VERSION 5.7 ;
BUSBITCHARS "[]" ;
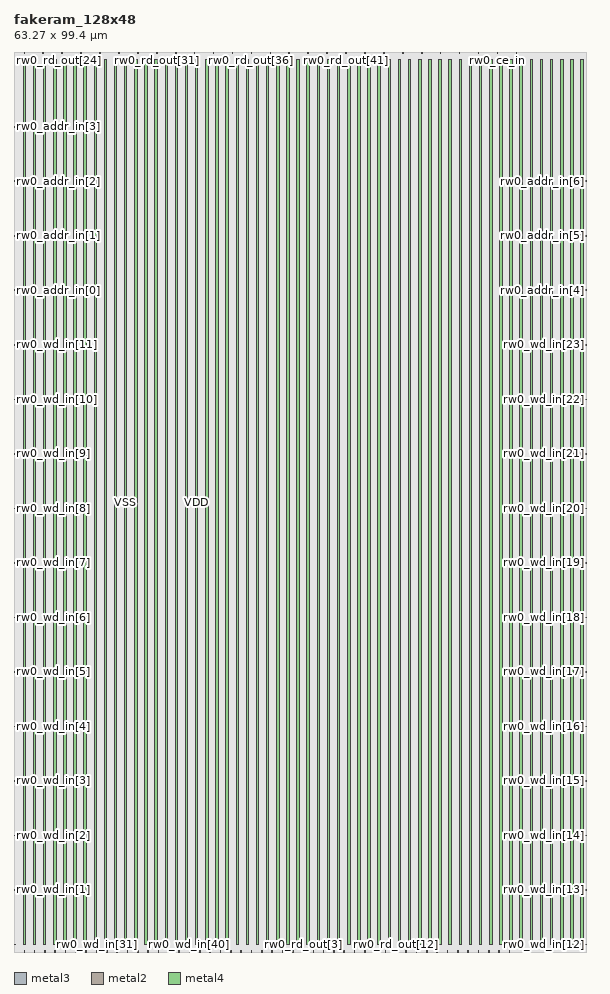
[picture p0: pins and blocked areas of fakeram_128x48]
MACRO fakeram_128x48
  FOREIGN fakeram_128x48 0 0 ;
  SYMMETRY X Y R90 ;
  SIZE 63.270 BY 99.400 ;
  CLASS BLOCK ;
  PIN rw0_wd_in[0]
    DIRECTION INPUT ;
    USE SIGNAL ;
    SHAPE ABUTMENT ;
    PORT
      LAYER metal3 ;
      RECT 0.000 0.805 0.210 0.875 ;
    END
  END rw0_wd_in[0]
  PIN rw0_wd_in[1]
    DIRECTION INPUT ;
    USE SIGNAL ;
    SHAPE ABUTMENT ;
    PORT
      LAYER metal3 ;
      RECT 0.000 6.825 0.210 6.895 ;
    END
  END rw0_wd_in[1]
  PIN rw0_wd_in[2]
    DIRECTION INPUT ;
    USE SIGNAL ;
    SHAPE ABUTMENT ;
    PORT
      LAYER metal3 ;
      RECT 0.000 12.845 0.210 12.915 ;
    END
  END rw0_wd_in[2]
  PIN rw0_wd_in[3]
    DIRECTION INPUT ;
    USE SIGNAL ;
    SHAPE ABUTMENT ;
    PORT
      LAYER metal3 ;
      RECT 0.000 18.865 0.210 18.935 ;
    END
  END rw0_wd_in[3]
  PIN rw0_wd_in[4]
    DIRECTION INPUT ;
    USE SIGNAL ;
    SHAPE ABUTMENT ;
    PORT
      LAYER metal3 ;
      RECT 0.000 24.885 0.210 24.955 ;
    END
  END rw0_wd_in[4]
  PIN rw0_wd_in[5]
    DIRECTION INPUT ;
    USE SIGNAL ;
    SHAPE ABUTMENT ;
    PORT
      LAYER metal3 ;
      RECT 0.000 30.905 0.210 30.975 ;
    END
  END rw0_wd_in[5]
  PIN rw0_wd_in[6]
    DIRECTION INPUT ;
    USE SIGNAL ;
    SHAPE ABUTMENT ;
    PORT
      LAYER metal3 ;
      RECT 0.000 36.925 0.210 36.995 ;
    END
  END rw0_wd_in[6]
  PIN rw0_wd_in[7]
    DIRECTION INPUT ;
    USE SIGNAL ;
    SHAPE ABUTMENT ;
    PORT
      LAYER metal3 ;
      RECT 0.000 42.945 0.210 43.015 ;
    END
  END rw0_wd_in[7]
  PIN rw0_wd_in[8]
    DIRECTION INPUT ;
    USE SIGNAL ;
    SHAPE ABUTMENT ;
    PORT
      LAYER metal3 ;
      RECT 0.000 48.965 0.210 49.035 ;
    END
  END rw0_wd_in[8]
  PIN rw0_wd_in[9]
    DIRECTION INPUT ;
    USE SIGNAL ;
    SHAPE ABUTMENT ;
    PORT
      LAYER metal3 ;
      RECT 0.000 54.985 0.210 55.055 ;
    END
  END rw0_wd_in[9]
  PIN rw0_wd_in[10]
    DIRECTION INPUT ;
    USE SIGNAL ;
    SHAPE ABUTMENT ;
    PORT
      LAYER metal3 ;
      RECT 0.000 61.005 0.210 61.075 ;
    END
  END rw0_wd_in[10]
  PIN rw0_wd_in[11]
    DIRECTION INPUT ;
    USE SIGNAL ;
    SHAPE ABUTMENT ;
    PORT
      LAYER metal3 ;
      RECT 0.000 67.025 0.210 67.095 ;
    END
  END rw0_wd_in[11]
  PIN rw0_wd_in[12]
    DIRECTION INPUT ;
    USE SIGNAL ;
    SHAPE ABUTMENT ;
    PORT
      LAYER metal3 ;
      RECT 63.060 0.805 63.270 0.875 ;
    END
  END rw0_wd_in[12]
  PIN rw0_wd_in[13]
    DIRECTION INPUT ;
    USE SIGNAL ;
    SHAPE ABUTMENT ;
    PORT
      LAYER metal3 ;
      RECT 63.060 6.825 63.270 6.895 ;
    END
  END rw0_wd_in[13]
  PIN rw0_wd_in[14]
    DIRECTION INPUT ;
    USE SIGNAL ;
    SHAPE ABUTMENT ;
    PORT
      LAYER metal3 ;
      RECT 63.060 12.845 63.270 12.915 ;
    END
  END rw0_wd_in[14]
  PIN rw0_wd_in[15]
    DIRECTION INPUT ;
    USE SIGNAL ;
    SHAPE ABUTMENT ;
    PORT
      LAYER metal3 ;
      RECT 63.060 18.865 63.270 18.935 ;
    END
  END rw0_wd_in[15]
  PIN rw0_wd_in[16]
    DIRECTION INPUT ;
    USE SIGNAL ;
    SHAPE ABUTMENT ;
    PORT
      LAYER metal3 ;
      RECT 63.060 24.885 63.270 24.955 ;
    END
  END rw0_wd_in[16]
  PIN rw0_wd_in[17]
    DIRECTION INPUT ;
    USE SIGNAL ;
    SHAPE ABUTMENT ;
    PORT
      LAYER metal3 ;
      RECT 63.060 30.905 63.270 30.975 ;
    END
  END rw0_wd_in[17]
  PIN rw0_wd_in[18]
    DIRECTION INPUT ;
    USE SIGNAL ;
    SHAPE ABUTMENT ;
    PORT
      LAYER metal3 ;
      RECT 63.060 36.925 63.270 36.995 ;
    END
  END rw0_wd_in[18]
  PIN rw0_wd_in[19]
    DIRECTION INPUT ;
    USE SIGNAL ;
    SHAPE ABUTMENT ;
    PORT
      LAYER metal3 ;
      RECT 63.060 42.945 63.270 43.015 ;
    END
  END rw0_wd_in[19]
  PIN rw0_wd_in[20]
    DIRECTION INPUT ;
    USE SIGNAL ;
    SHAPE ABUTMENT ;
    PORT
      LAYER metal3 ;
      RECT 63.060 48.965 63.270 49.035 ;
    END
  END rw0_wd_in[20]
  PIN rw0_wd_in[21]
    DIRECTION INPUT ;
    USE SIGNAL ;
    SHAPE ABUTMENT ;
    PORT
      LAYER metal3 ;
      RECT 63.060 54.985 63.270 55.055 ;
    END
  END rw0_wd_in[21]
  PIN rw0_wd_in[22]
    DIRECTION INPUT ;
    USE SIGNAL ;
    SHAPE ABUTMENT ;
    PORT
      LAYER metal3 ;
      RECT 63.060 61.005 63.270 61.075 ;
    END
  END rw0_wd_in[22]
  PIN rw0_wd_in[23]
    DIRECTION INPUT ;
    USE SIGNAL ;
    SHAPE ABUTMENT ;
    PORT
      LAYER metal3 ;
      RECT 63.060 67.025 63.270 67.095 ;
    END
  END rw0_wd_in[23]
  PIN rw0_wd_in[24]
    DIRECTION INPUT ;
    USE SIGNAL ;
    SHAPE ABUTMENT ;
    PORT
      LAYER metal2 ;
      RECT 1.105 0.000 1.175 0.210 ;
    END
  END rw0_wd_in[24]
  PIN rw0_wd_in[25]
    DIRECTION INPUT ;
    USE SIGNAL ;
    SHAPE ABUTMENT ;
    PORT
      LAYER metal2 ;
      RECT 2.245 0.000 2.315 0.210 ;
    END
  END rw0_wd_in[25]
  PIN rw0_wd_in[26]
    DIRECTION INPUT ;
    USE SIGNAL ;
    SHAPE ABUTMENT ;
    PORT
      LAYER metal2 ;
      RECT 3.385 0.000 3.455 0.210 ;
    END
  END rw0_wd_in[26]
  PIN rw0_wd_in[27]
    DIRECTION INPUT ;
    USE SIGNAL ;
    SHAPE ABUTMENT ;
    PORT
      LAYER metal2 ;
      RECT 4.525 0.000 4.595 0.210 ;
    END
  END rw0_wd_in[27]
  PIN rw0_wd_in[28]
    DIRECTION INPUT ;
    USE SIGNAL ;
    SHAPE ABUTMENT ;
    PORT
      LAYER metal2 ;
      RECT 5.665 0.000 5.735 0.210 ;
    END
  END rw0_wd_in[28]
  PIN rw0_wd_in[29]
    DIRECTION INPUT ;
    USE SIGNAL ;
    SHAPE ABUTMENT ;
    PORT
      LAYER metal2 ;
      RECT 6.805 0.000 6.875 0.210 ;
    END
  END rw0_wd_in[29]
  PIN rw0_wd_in[30]
    DIRECTION INPUT ;
    USE SIGNAL ;
    SHAPE ABUTMENT ;
    PORT
      LAYER metal2 ;
      RECT 7.945 0.000 8.015 0.210 ;
    END
  END rw0_wd_in[30]
  PIN rw0_wd_in[31]
    DIRECTION INPUT ;
    USE SIGNAL ;
    SHAPE ABUTMENT ;
    PORT
      LAYER metal2 ;
      RECT 9.085 0.000 9.155 0.210 ;
    END
  END rw0_wd_in[31]
  PIN rw0_wd_in[32]
    DIRECTION INPUT ;
    USE SIGNAL ;
    SHAPE ABUTMENT ;
    PORT
      LAYER metal2 ;
      RECT 10.225 0.000 10.295 0.210 ;
    END
  END rw0_wd_in[32]
  PIN rw0_wd_in[33]
    DIRECTION INPUT ;
    USE SIGNAL ;
    SHAPE ABUTMENT ;
    PORT
      LAYER metal2 ;
      RECT 11.365 0.000 11.435 0.210 ;
    END
  END rw0_wd_in[33]
  PIN rw0_wd_in[34]
    DIRECTION INPUT ;
    USE SIGNAL ;
    SHAPE ABUTMENT ;
    PORT
      LAYER metal2 ;
      RECT 12.505 0.000 12.575 0.210 ;
    END
  END rw0_wd_in[34]
  PIN rw0_wd_in[35]
    DIRECTION INPUT ;
    USE SIGNAL ;
    SHAPE ABUTMENT ;
    PORT
      LAYER metal2 ;
      RECT 13.645 0.000 13.715 0.210 ;
    END
  END rw0_wd_in[35]
  PIN rw0_wd_in[36]
    DIRECTION INPUT ;
    USE SIGNAL ;
    SHAPE ABUTMENT ;
    PORT
      LAYER metal2 ;
      RECT 14.785 0.000 14.855 0.210 ;
    END
  END rw0_wd_in[36]
  PIN rw0_wd_in[37]
    DIRECTION INPUT ;
    USE SIGNAL ;
    SHAPE ABUTMENT ;
    PORT
      LAYER metal2 ;
      RECT 15.925 0.000 15.995 0.210 ;
    END
  END rw0_wd_in[37]
  PIN rw0_wd_in[38]
    DIRECTION INPUT ;
    USE SIGNAL ;
    SHAPE ABUTMENT ;
    PORT
      LAYER metal2 ;
      RECT 17.065 0.000 17.135 0.210 ;
    END
  END rw0_wd_in[38]
  PIN rw0_wd_in[39]
    DIRECTION INPUT ;
    USE SIGNAL ;
    SHAPE ABUTMENT ;
    PORT
      LAYER metal2 ;
      RECT 18.205 0.000 18.275 0.210 ;
    END
  END rw0_wd_in[39]
  PIN rw0_wd_in[40]
    DIRECTION INPUT ;
    USE SIGNAL ;
    SHAPE ABUTMENT ;
    PORT
      LAYER metal2 ;
      RECT 19.345 0.000 19.415 0.210 ;
    END
  END rw0_wd_in[40]
  PIN rw0_wd_in[41]
    DIRECTION INPUT ;
    USE SIGNAL ;
    SHAPE ABUTMENT ;
    PORT
      LAYER metal2 ;
      RECT 20.485 0.000 20.555 0.210 ;
    END
  END rw0_wd_in[41]
  PIN rw0_wd_in[42]
    DIRECTION INPUT ;
    USE SIGNAL ;
    SHAPE ABUTMENT ;
    PORT
      LAYER metal2 ;
      RECT 21.625 0.000 21.695 0.210 ;
    END
  END rw0_wd_in[42]
  PIN rw0_wd_in[43]
    DIRECTION INPUT ;
    USE SIGNAL ;
    SHAPE ABUTMENT ;
    PORT
      LAYER metal2 ;
      RECT 22.765 0.000 22.835 0.210 ;
    END
  END rw0_wd_in[43]
  PIN rw0_wd_in[44]
    DIRECTION INPUT ;
    USE SIGNAL ;
    SHAPE ABUTMENT ;
    PORT
      LAYER metal2 ;
      RECT 23.905 0.000 23.975 0.210 ;
    END
  END rw0_wd_in[44]
  PIN rw0_wd_in[45]
    DIRECTION INPUT ;
    USE SIGNAL ;
    SHAPE ABUTMENT ;
    PORT
      LAYER metal2 ;
      RECT 25.045 0.000 25.115 0.210 ;
    END
  END rw0_wd_in[45]
  PIN rw0_wd_in[46]
    DIRECTION INPUT ;
    USE SIGNAL ;
    SHAPE ABUTMENT ;
    PORT
      LAYER metal2 ;
      RECT 26.185 0.000 26.255 0.210 ;
    END
  END rw0_wd_in[46]
  PIN rw0_wd_in[47]
    DIRECTION INPUT ;
    USE SIGNAL ;
    SHAPE ABUTMENT ;
    PORT
      LAYER metal2 ;
      RECT 27.325 0.000 27.395 0.210 ;
    END
  END rw0_wd_in[47]
  PIN rw0_rd_out[0]
    DIRECTION OUTPUT ;
    USE SIGNAL ;
    SHAPE ABUTMENT ;
    PORT
      LAYER metal2 ;
      RECT 28.465 0.000 28.535 0.210 ;
    END
  END rw0_rd_out[0]
  PIN rw0_rd_out[1]
    DIRECTION OUTPUT ;
    USE SIGNAL ;
    SHAPE ABUTMENT ;
    PORT
      LAYER metal2 ;
      RECT 29.605 0.000 29.675 0.210 ;
    END
  END rw0_rd_out[1]
  PIN rw0_rd_out[2]
    DIRECTION OUTPUT ;
    USE SIGNAL ;
    SHAPE ABUTMENT ;
    PORT
      LAYER metal2 ;
      RECT 30.745 0.000 30.815 0.210 ;
    END
  END rw0_rd_out[2]
  PIN rw0_rd_out[3]
    DIRECTION OUTPUT ;
    USE SIGNAL ;
    SHAPE ABUTMENT ;
    PORT
      LAYER metal2 ;
      RECT 31.885 0.000 31.955 0.210 ;
    END
  END rw0_rd_out[3]
  PIN rw0_rd_out[4]
    DIRECTION OUTPUT ;
    USE SIGNAL ;
    SHAPE ABUTMENT ;
    PORT
      LAYER metal2 ;
      RECT 33.025 0.000 33.095 0.210 ;
    END
  END rw0_rd_out[4]
  PIN rw0_rd_out[5]
    DIRECTION OUTPUT ;
    USE SIGNAL ;
    SHAPE ABUTMENT ;
    PORT
      LAYER metal2 ;
      RECT 34.165 0.000 34.235 0.210 ;
    END
  END rw0_rd_out[5]
  PIN rw0_rd_out[6]
    DIRECTION OUTPUT ;
    USE SIGNAL ;
    SHAPE ABUTMENT ;
    PORT
      LAYER metal2 ;
      RECT 35.305 0.000 35.375 0.210 ;
    END
  END rw0_rd_out[6]
  PIN rw0_rd_out[7]
    DIRECTION OUTPUT ;
    USE SIGNAL ;
    SHAPE ABUTMENT ;
    PORT
      LAYER metal2 ;
      RECT 36.445 0.000 36.515 0.210 ;
    END
  END rw0_rd_out[7]
  PIN rw0_rd_out[8]
    DIRECTION OUTPUT ;
    USE SIGNAL ;
    SHAPE ABUTMENT ;
    PORT
      LAYER metal2 ;
      RECT 37.585 0.000 37.655 0.210 ;
    END
  END rw0_rd_out[8]
  PIN rw0_rd_out[9]
    DIRECTION OUTPUT ;
    USE SIGNAL ;
    SHAPE ABUTMENT ;
    PORT
      LAYER metal2 ;
      RECT 38.725 0.000 38.795 0.210 ;
    END
  END rw0_rd_out[9]
  PIN rw0_rd_out[10]
    DIRECTION OUTPUT ;
    USE SIGNAL ;
    SHAPE ABUTMENT ;
    PORT
      LAYER metal2 ;
      RECT 39.865 0.000 39.935 0.210 ;
    END
  END rw0_rd_out[10]
  PIN rw0_rd_out[11]
    DIRECTION OUTPUT ;
    USE SIGNAL ;
    SHAPE ABUTMENT ;
    PORT
      LAYER metal2 ;
      RECT 41.005 0.000 41.075 0.210 ;
    END
  END rw0_rd_out[11]
  PIN rw0_rd_out[12]
    DIRECTION OUTPUT ;
    USE SIGNAL ;
    SHAPE ABUTMENT ;
    PORT
      LAYER metal2 ;
      RECT 42.145 0.000 42.215 0.210 ;
    END
  END rw0_rd_out[12]
  PIN rw0_rd_out[13]
    DIRECTION OUTPUT ;
    USE SIGNAL ;
    SHAPE ABUTMENT ;
    PORT
      LAYER metal2 ;
      RECT 43.285 0.000 43.355 0.210 ;
    END
  END rw0_rd_out[13]
  PIN rw0_rd_out[14]
    DIRECTION OUTPUT ;
    USE SIGNAL ;
    SHAPE ABUTMENT ;
    PORT
      LAYER metal2 ;
      RECT 44.425 0.000 44.495 0.210 ;
    END
  END rw0_rd_out[14]
  PIN rw0_rd_out[15]
    DIRECTION OUTPUT ;
    USE SIGNAL ;
    SHAPE ABUTMENT ;
    PORT
      LAYER metal2 ;
      RECT 45.565 0.000 45.635 0.210 ;
    END
  END rw0_rd_out[15]
  PIN rw0_rd_out[16]
    DIRECTION OUTPUT ;
    USE SIGNAL ;
    SHAPE ABUTMENT ;
    PORT
      LAYER metal2 ;
      RECT 46.705 0.000 46.775 0.210 ;
    END
  END rw0_rd_out[16]
  PIN rw0_rd_out[17]
    DIRECTION OUTPUT ;
    USE SIGNAL ;
    SHAPE ABUTMENT ;
    PORT
      LAYER metal2 ;
      RECT 47.845 0.000 47.915 0.210 ;
    END
  END rw0_rd_out[17]
  PIN rw0_rd_out[18]
    DIRECTION OUTPUT ;
    USE SIGNAL ;
    SHAPE ABUTMENT ;
    PORT
      LAYER metal2 ;
      RECT 48.985 0.000 49.055 0.210 ;
    END
  END rw0_rd_out[18]
  PIN rw0_rd_out[19]
    DIRECTION OUTPUT ;
    USE SIGNAL ;
    SHAPE ABUTMENT ;
    PORT
      LAYER metal2 ;
      RECT 50.125 0.000 50.195 0.210 ;
    END
  END rw0_rd_out[19]
  PIN rw0_rd_out[20]
    DIRECTION OUTPUT ;
    USE SIGNAL ;
    SHAPE ABUTMENT ;
    PORT
      LAYER metal2 ;
      RECT 51.265 0.000 51.335 0.210 ;
    END
  END rw0_rd_out[20]
  PIN rw0_rd_out[21]
    DIRECTION OUTPUT ;
    USE SIGNAL ;
    SHAPE ABUTMENT ;
    PORT
      LAYER metal2 ;
      RECT 52.405 0.000 52.475 0.210 ;
    END
  END rw0_rd_out[21]
  PIN rw0_rd_out[22]
    DIRECTION OUTPUT ;
    USE SIGNAL ;
    SHAPE ABUTMENT ;
    PORT
      LAYER metal2 ;
      RECT 53.545 0.000 53.615 0.210 ;
    END
  END rw0_rd_out[22]
  PIN rw0_rd_out[23]
    DIRECTION OUTPUT ;
    USE SIGNAL ;
    SHAPE ABUTMENT ;
    PORT
      LAYER metal2 ;
      RECT 54.685 0.000 54.755 0.210 ;
    END
  END rw0_rd_out[23]
  PIN rw0_rd_out[24]
    DIRECTION OUTPUT ;
    USE SIGNAL ;
    SHAPE ABUTMENT ;
    PORT
      LAYER metal2 ;
      RECT 1.105 99.190 1.175 99.400 ;
    END
  END rw0_rd_out[24]
  PIN rw0_rd_out[25]
    DIRECTION OUTPUT ;
    USE SIGNAL ;
    SHAPE ABUTMENT ;
    PORT
      LAYER metal2 ;
      RECT 3.195 99.190 3.265 99.400 ;
    END
  END rw0_rd_out[25]
  PIN rw0_rd_out[26]
    DIRECTION OUTPUT ;
    USE SIGNAL ;
    SHAPE ABUTMENT ;
    PORT
      LAYER metal2 ;
      RECT 5.285 99.190 5.355 99.400 ;
    END
  END rw0_rd_out[26]
  PIN rw0_rd_out[27]
    DIRECTION OUTPUT ;
    USE SIGNAL ;
    SHAPE ABUTMENT ;
    PORT
      LAYER metal2 ;
      RECT 7.375 99.190 7.445 99.400 ;
    END
  END rw0_rd_out[27]
  PIN rw0_rd_out[28]
    DIRECTION OUTPUT ;
    USE SIGNAL ;
    SHAPE ABUTMENT ;
    PORT
      LAYER metal2 ;
      RECT 9.465 99.190 9.535 99.400 ;
    END
  END rw0_rd_out[28]
  PIN rw0_rd_out[29]
    DIRECTION OUTPUT ;
    USE SIGNAL ;
    SHAPE ABUTMENT ;
    PORT
      LAYER metal2 ;
      RECT 11.555 99.190 11.625 99.400 ;
    END
  END rw0_rd_out[29]
  PIN rw0_rd_out[30]
    DIRECTION OUTPUT ;
    USE SIGNAL ;
    SHAPE ABUTMENT ;
    PORT
      LAYER metal2 ;
      RECT 13.645 99.190 13.715 99.400 ;
    END
  END rw0_rd_out[30]
  PIN rw0_rd_out[31]
    DIRECTION OUTPUT ;
    USE SIGNAL ;
    SHAPE ABUTMENT ;
    PORT
      LAYER metal2 ;
      RECT 15.735 99.190 15.805 99.400 ;
    END
  END rw0_rd_out[31]
  PIN rw0_rd_out[32]
    DIRECTION OUTPUT ;
    USE SIGNAL ;
    SHAPE ABUTMENT ;
    PORT
      LAYER metal2 ;
      RECT 17.825 99.190 17.895 99.400 ;
    END
  END rw0_rd_out[32]
  PIN rw0_rd_out[33]
    DIRECTION OUTPUT ;
    USE SIGNAL ;
    SHAPE ABUTMENT ;
    PORT
      LAYER metal2 ;
      RECT 19.915 99.190 19.985 99.400 ;
    END
  END rw0_rd_out[33]
  PIN rw0_rd_out[34]
    DIRECTION OUTPUT ;
    USE SIGNAL ;
    SHAPE ABUTMENT ;
    PORT
      LAYER metal2 ;
      RECT 22.005 99.190 22.075 99.400 ;
    END
  END rw0_rd_out[34]
  PIN rw0_rd_out[35]
    DIRECTION OUTPUT ;
    USE SIGNAL ;
    SHAPE ABUTMENT ;
    PORT
      LAYER metal2 ;
      RECT 24.095 99.190 24.165 99.400 ;
    END
  END rw0_rd_out[35]
  PIN rw0_rd_out[36]
    DIRECTION OUTPUT ;
    USE SIGNAL ;
    SHAPE ABUTMENT ;
    PORT
      LAYER metal2 ;
      RECT 26.185 99.190 26.255 99.400 ;
    END
  END rw0_rd_out[36]
  PIN rw0_rd_out[37]
    DIRECTION OUTPUT ;
    USE SIGNAL ;
    SHAPE ABUTMENT ;
    PORT
      LAYER metal2 ;
      RECT 28.275 99.190 28.345 99.400 ;
    END
  END rw0_rd_out[37]
  PIN rw0_rd_out[38]
    DIRECTION OUTPUT ;
    USE SIGNAL ;
    SHAPE ABUTMENT ;
    PORT
      LAYER metal2 ;
      RECT 30.365 99.190 30.435 99.400 ;
    END
  END rw0_rd_out[38]
  PIN rw0_rd_out[39]
    DIRECTION OUTPUT ;
    USE SIGNAL ;
    SHAPE ABUTMENT ;
    PORT
      LAYER metal2 ;
      RECT 32.455 99.190 32.525 99.400 ;
    END
  END rw0_rd_out[39]
  PIN rw0_rd_out[40]
    DIRECTION OUTPUT ;
    USE SIGNAL ;
    SHAPE ABUTMENT ;
    PORT
      LAYER metal2 ;
      RECT 34.545 99.190 34.615 99.400 ;
    END
  END rw0_rd_out[40]
  PIN rw0_rd_out[41]
    DIRECTION OUTPUT ;
    USE SIGNAL ;
    SHAPE ABUTMENT ;
    PORT
      LAYER metal2 ;
      RECT 36.635 99.190 36.705 99.400 ;
    END
  END rw0_rd_out[41]
  PIN rw0_rd_out[42]
    DIRECTION OUTPUT ;
    USE SIGNAL ;
    SHAPE ABUTMENT ;
    PORT
      LAYER metal2 ;
      RECT 38.725 99.190 38.795 99.400 ;
    END
  END rw0_rd_out[42]
  PIN rw0_rd_out[43]
    DIRECTION OUTPUT ;
    USE SIGNAL ;
    SHAPE ABUTMENT ;
    PORT
      LAYER metal2 ;
      RECT 40.815 99.190 40.885 99.400 ;
    END
  END rw0_rd_out[43]
  PIN rw0_rd_out[44]
    DIRECTION OUTPUT ;
    USE SIGNAL ;
    SHAPE ABUTMENT ;
    PORT
      LAYER metal2 ;
      RECT 42.905 99.190 42.975 99.400 ;
    END
  END rw0_rd_out[44]
  PIN rw0_rd_out[45]
    DIRECTION OUTPUT ;
    USE SIGNAL ;
    SHAPE ABUTMENT ;
    PORT
      LAYER metal2 ;
      RECT 44.995 99.190 45.065 99.400 ;
    END
  END rw0_rd_out[45]
  PIN rw0_rd_out[46]
    DIRECTION OUTPUT ;
    USE SIGNAL ;
    SHAPE ABUTMENT ;
    PORT
      LAYER metal2 ;
      RECT 47.085 99.190 47.155 99.400 ;
    END
  END rw0_rd_out[46]
  PIN rw0_rd_out[47]
    DIRECTION OUTPUT ;
    USE SIGNAL ;
    SHAPE ABUTMENT ;
    PORT
      LAYER metal2 ;
      RECT 49.175 99.190 49.245 99.400 ;
    END
  END rw0_rd_out[47]
  PIN rw0_addr_in[0]
    DIRECTION INPUT ;
    USE SIGNAL ;
    SHAPE ABUTMENT ;
    PORT
      LAYER metal3 ;
      RECT 0.000 73.045 0.210 73.115 ;
    END
  END rw0_addr_in[0]
  PIN rw0_addr_in[1]
    DIRECTION INPUT ;
    USE SIGNAL ;
    SHAPE ABUTMENT ;
    PORT
      LAYER metal3 ;
      RECT 0.000 79.065 0.210 79.135 ;
    END
  END rw0_addr_in[1]
  PIN rw0_addr_in[2]
    DIRECTION INPUT ;
    USE SIGNAL ;
    SHAPE ABUTMENT ;
    PORT
      LAYER metal3 ;
      RECT 0.000 85.085 0.210 85.155 ;
    END
  END rw0_addr_in[2]
  PIN rw0_addr_in[3]
    DIRECTION INPUT ;
    USE SIGNAL ;
    SHAPE ABUTMENT ;
    PORT
      LAYER metal3 ;
      RECT 0.000 91.105 0.210 91.175 ;
    END
  END rw0_addr_in[3]
  PIN rw0_addr_in[4]
    DIRECTION INPUT ;
    USE SIGNAL ;
    SHAPE ABUTMENT ;
    PORT
      LAYER metal3 ;
      RECT 63.060 73.045 63.270 73.115 ;
    END
  END rw0_addr_in[4]
  PIN rw0_addr_in[5]
    DIRECTION INPUT ;
    USE SIGNAL ;
    SHAPE ABUTMENT ;
    PORT
      LAYER metal3 ;
      RECT 63.060 79.065 63.270 79.135 ;
    END
  END rw0_addr_in[5]
  PIN rw0_addr_in[6]
    DIRECTION INPUT ;
    USE SIGNAL ;
    SHAPE ABUTMENT ;
    PORT
      LAYER metal3 ;
      RECT 63.060 85.085 63.270 85.155 ;
    END
  END rw0_addr_in[6]
  PIN rw0_we_in
    DIRECTION INPUT ;
    USE SIGNAL ;
    SHAPE ABUTMENT ;
    PORT
      LAYER metal2 ;
      RECT 51.265 99.190 51.335 99.400 ;
    END
  END rw0_we_in
  PIN rw0_ce_in
    DIRECTION INPUT ;
    USE SIGNAL ;
    SHAPE ABUTMENT ;
    PORT
      LAYER metal2 ;
      RECT 53.355 99.190 53.425 99.400 ;
    END
  END rw0_ce_in
  PIN rw0_clk
    DIRECTION INPUT ;
    USE SIGNAL ;
    SHAPE ABUTMENT ;
    PORT
      LAYER metal2 ;
      RECT 55.445 99.190 55.515 99.400 ;
    END
  END rw0_clk
  PIN VSS
    DIRECTION INOUT ;
    USE GROUND ;
    PORT
      LAYER metal4 ;
      RECT 1.000 0.840 1.280 98.560 ;
      RECT 3.240 0.840 3.520 98.560 ;
      RECT 5.480 0.840 5.760 98.560 ;
      RECT 7.720 0.840 8.000 98.560 ;
      RECT 9.960 0.840 10.240 98.560 ;
      RECT 12.200 0.840 12.480 98.560 ;
      RECT 14.440 0.840 14.720 98.560 ;
      RECT 16.680 0.840 16.960 98.560 ;
      RECT 18.920 0.840 19.200 98.560 ;
      RECT 21.160 0.840 21.440 98.560 ;
      RECT 23.400 0.840 23.680 98.560 ;
      RECT 25.640 0.840 25.920 98.560 ;
      RECT 27.880 0.840 28.160 98.560 ;
      RECT 30.120 0.840 30.400 98.560 ;
      RECT 32.360 0.840 32.640 98.560 ;
      RECT 34.600 0.840 34.880 98.560 ;
      RECT 36.840 0.840 37.120 98.560 ;
      RECT 39.080 0.840 39.360 98.560 ;
      RECT 41.320 0.840 41.600 98.560 ;
      RECT 43.560 0.840 43.840 98.560 ;
      RECT 45.800 0.840 46.080 98.560 ;
      RECT 48.040 0.840 48.320 98.560 ;
      RECT 50.280 0.840 50.560 98.560 ;
      RECT 52.520 0.840 52.800 98.560 ;
      RECT 54.760 0.840 55.040 98.560 ;
      RECT 57.000 0.840 57.280 98.560 ;
      RECT 59.240 0.840 59.520 98.560 ;
      RECT 61.480 0.840 61.760 98.560 ;
    END
  END VSS
  PIN VDD
    DIRECTION INOUT ;
    USE POWER ;
    PORT
      LAYER metal4 ;
      RECT 2.120 0.840 2.400 98.560 ;
      RECT 4.360 0.840 4.640 98.560 ;
      RECT 6.600 0.840 6.880 98.560 ;
      RECT 8.840 0.840 9.120 98.560 ;
      RECT 11.080 0.840 11.360 98.560 ;
      RECT 13.320 0.840 13.600 98.560 ;
      RECT 15.560 0.840 15.840 98.560 ;
      RECT 17.800 0.840 18.080 98.560 ;
      RECT 20.040 0.840 20.320 98.560 ;
      RECT 22.280 0.840 22.560 98.560 ;
      RECT 24.520 0.840 24.800 98.560 ;
      RECT 26.760 0.840 27.040 98.560 ;
      RECT 29.000 0.840 29.280 98.560 ;
      RECT 31.240 0.840 31.520 98.560 ;
      RECT 33.480 0.840 33.760 98.560 ;
      RECT 35.720 0.840 36.000 98.560 ;
      RECT 37.960 0.840 38.240 98.560 ;
      RECT 40.200 0.840 40.480 98.560 ;
      RECT 42.440 0.840 42.720 98.560 ;
      RECT 44.680 0.840 44.960 98.560 ;
      RECT 46.920 0.840 47.200 98.560 ;
      RECT 49.160 0.840 49.440 98.560 ;
      RECT 51.400 0.840 51.680 98.560 ;
      RECT 53.640 0.840 53.920 98.560 ;
      RECT 55.880 0.840 56.160 98.560 ;
      RECT 58.120 0.840 58.400 98.560 ;
      RECT 60.360 0.840 60.640 98.560 ;
      RECT 62.600 0.840 62.880 98.560 ;
    END
  END VDD
  OBS
    LAYER metal1 ;
    RECT 0 0 63.270 99.400 ;
    LAYER metal2 ;
    RECT 0 0 63.270 99.400 ;
    LAYER metal3 ;
    RECT 0 0 63.270 99.400 ;
    LAYER metal4 ;
    RECT 0 0 63.270 99.400 ;
    LAYER OVERLAP ;
    RECT 0 0 63.270 99.400 ;
  END
END fakeram_128x48

END LIBRARY
